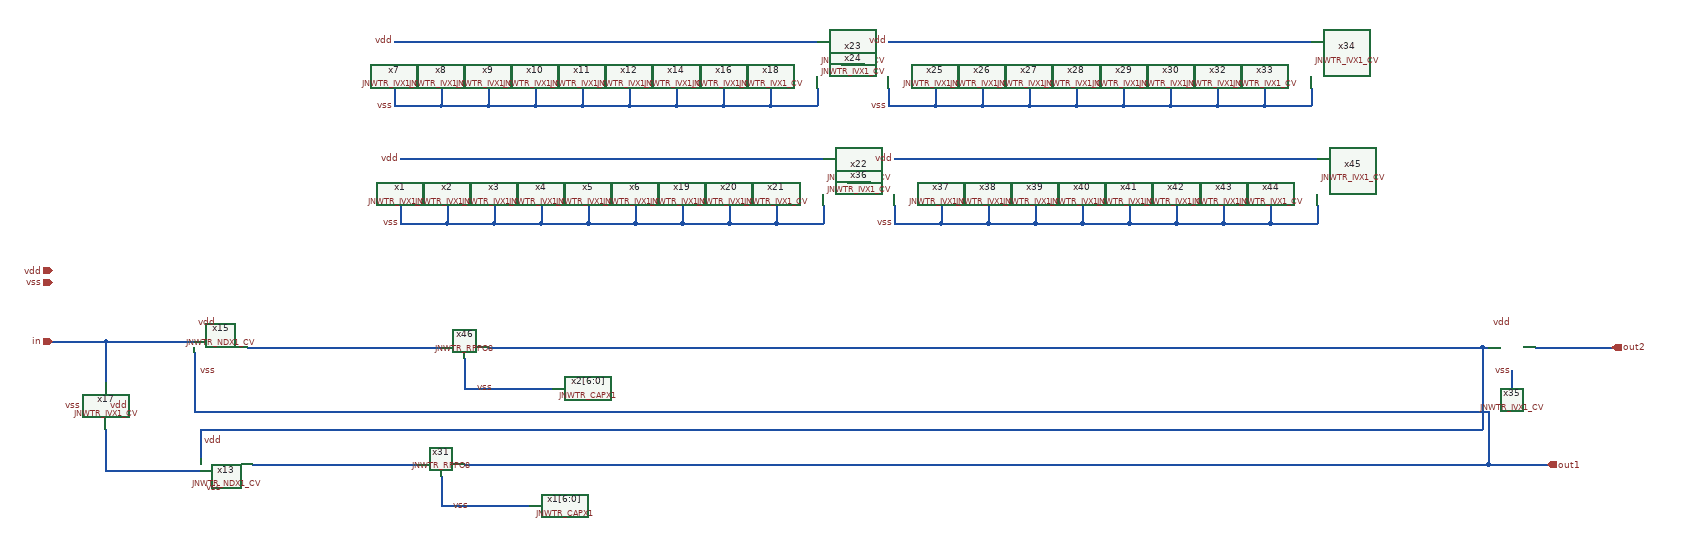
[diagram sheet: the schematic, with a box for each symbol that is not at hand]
v {xschem version=3.4.5 file_version=1.2
}
G {}
K {}
V {}
S {}
E {}
N 170 -220 170 -150 {
lab=#net1}
N 170 -150 330 -150 {
lab=#net1}
N 170 -370 320 -370 {
lab=in}
N 170 -370 170 -300 {
lab=in}
N 80 -370 170 -370 {
lab=in}
N 320 -250 2520 -250 {
lab=out1}
N 320 -350 320 -250 {
lab=out1}
N 330 -220 330 -170 {
lab=#net2}
N 2560 -320 2560 -290 {
lab=vss}
N 2520 -250 2520 -160 {
lab=out1}
N 660 -800 660 -770 {
lab=vss}
N 740 -800 740 -770 {
lab=vss}
N 820 -800 820 -770 {
lab=vss}
N 900 -800 900 -770 {
lab=vss}
N 980 -800 980 -770 {
lab=vss}
N 1060 -800 1060 -770 {
lab=vss}
N 980 -770 1060 -770 {
lab=vss}
N 660 -770 740 -770 {
lab=vss}
N 740 -770 820 -770 {
lab=vss}
N 820 -770 900 -770 {
lab=vss}
N 900 -770 980 -770 {
lab=vss}
N 2510 -360 2510 -220 {
lab=#net2}
N 2520 -160 2620 -160 {
lab=out1}
N 2600 -360 2730 -360 {
lab=out2}
N 1140 -800 1140 -770 {
lab=vss}
N 1220 -800 1220 -770 {
lab=vss}
N 1220 -770 1300 -770 {
lab=vss}
N 1060 -770 1140 -770 {
lab=vss}
N 1140 -770 1220 -770 {
lab=vss}
N 660 -880 1380 -880 {
lab=vdd}
N 1300 -770 1380 -770 {
lab=vss}
N 1300 -800 1300 -770 {
lab=vss}
N 1380 -800 1380 -770 {
lab=vss}
N 740 -140 740 -90 {
lab=vss}
N 740 -90 890 -90 {
lab=vss}
N 2510 -360 2520 -360 {
lab=#net2}
N 330 -220 2510 -220 {
lab=#net2}
N 670 -600 670 -570 {
lab=vss}
N 750 -600 750 -570 {
lab=vss}
N 830 -600 830 -570 {
lab=vss}
N 910 -600 910 -570 {
lab=vss}
N 990 -600 990 -570 {
lab=vss}
N 1070 -600 1070 -570 {
lab=vss}
N 990 -570 1070 -570 {
lab=vss}
N 670 -570 750 -570 {
lab=vss}
N 750 -570 830 -570 {
lab=vss}
N 830 -570 910 -570 {
lab=vss}
N 910 -570 990 -570 {
lab=vss}
N 1150 -600 1150 -570 {
lab=vss}
N 1230 -600 1230 -570 {
lab=vss}
N 1230 -570 1310 -570 {
lab=vss}
N 1070 -570 1150 -570 {
lab=vss}
N 1150 -570 1230 -570 {
lab=vss}
N 670 -680 1390 -680 {
lab=vdd}
N 1310 -570 1390 -570 {
lab=vss}
N 1310 -600 1310 -570 {
lab=vss}
N 1390 -600 1390 -570 {
lab=vss}
N 1500 -800 1500 -770 {
lab=vss}
N 1580 -800 1580 -770 {
lab=vss}
N 1660 -800 1660 -770 {
lab=vss}
N 1740 -800 1740 -770 {
lab=vss}
N 1820 -800 1820 -770 {
lab=vss}
N 1900 -800 1900 -770 {
lab=vss}
N 1820 -770 1900 -770 {
lab=vss}
N 1500 -770 1580 -770 {
lab=vss}
N 1580 -770 1660 -770 {
lab=vss}
N 1660 -770 1740 -770 {
lab=vss}
N 1740 -770 1820 -770 {
lab=vss}
N 1980 -800 1980 -770 {
lab=vss}
N 2060 -800 2060 -770 {
lab=vss}
N 2060 -770 2140 -770 {
lab=vss}
N 1900 -770 1980 -770 {
lab=vss}
N 1980 -770 2060 -770 {
lab=vss}
N 1500 -880 2220 -880 {
lab=vdd}
N 2140 -770 2220 -770 {
lab=vss}
N 2140 -800 2140 -770 {
lab=vss}
N 2220 -800 2220 -770 {
lab=vss}
N 1510 -600 1510 -570 {
lab=vss}
N 1590 -600 1590 -570 {
lab=vss}
N 1670 -600 1670 -570 {
lab=vss}
N 1750 -600 1750 -570 {
lab=vss}
N 1830 -600 1830 -570 {
lab=vss}
N 1910 -600 1910 -570 {
lab=vss}
N 1830 -570 1910 -570 {
lab=vss}
N 1510 -570 1590 -570 {
lab=vss}
N 1590 -570 1670 -570 {
lab=vss}
N 1670 -570 1750 -570 {
lab=vss}
N 1750 -570 1830 -570 {
lab=vss}
N 1990 -600 1990 -570 {
lab=vss}
N 2070 -600 2070 -570 {
lab=vss}
N 2070 -570 2150 -570 {
lab=vss}
N 1910 -570 1990 -570 {
lab=vss}
N 1990 -570 2070 -570 {
lab=vss}
N 1510 -680 2230 -680 {
lab=vdd}
N 2150 -570 2230 -570 {
lab=vss}
N 2150 -600 2150 -570 {
lab=vss}
N 2230 -600 2230 -570 {
lab=vss}
N 1430 -640 1470 -640 {
lab=#net3}
N 1420 -840 1460 -840 {
lab=#net4}
N 420 -160 700 -160 {
lab=#net5}
N 780 -160 2520 -160 {
lab=out1}
N 780 -340 780 -290 {
lab=vss}
N 780 -290 930 -290 {
lab=vss}
N 410 -360 740 -360 {
lab=#net6}
N 820 -360 2510 -360 {
lab=#net2}
C {JNW_TR_SKY130A/JNWTR_NDX1_CV.sym} 330 -150 0 0 {name=x13 }
C {devices/lab_wire.sym} 370 -200 0 0 {name=p26 sig_type=std_logic lab=vdd}
C {devices/lab_wire.sym} 370 -120 0 0 {name=p27 sig_type=std_logic lab=vss
}
C {JNW_TR_SKY130A/JNWTR_NDX1_CV.sym} 320 -350 0 0 {name=x15 }
C {devices/lab_wire.sym} 360 -400 0 0 {name=p28 sig_type=std_logic lab=vdd}
C {devices/lab_wire.sym} 360 -320 0 0 {name=p30 sig_type=std_logic lab=vss
}
C {JNW_TR_SKY130A/JNWTR_IVX1_CV.sym} 170 -300 1 0 {name=x17 }
C {devices/lab_wire.sym} 130 -260 0 0 {name=p31 sig_type=std_logic lab=vss
}
C {devices/lab_wire.sym} 210 -260 0 0 {name=p33 sig_type=std_logic lab=vdd}
C {devices/ipin.sym} 80 -370 0 0 {name=p35 lab=in}
C {JNW_TR_SKY130A/JNWTR_IVX1_CV.sym} 2520 -360 0 0 {name=x35 }
C {devices/lab_wire.sym} 2560 -320 3 0 {name=p51 sig_type=std_logic lab=vss
}
C {devices/lab_wire.sym} 2560 -400 3 0 {name=p52 sig_type=std_logic lab=vdd}
C {devices/opin.sym} 2620 -160 0 0 {name=p1 lab=out1}
C {devices/opin.sym} 2730 -360 0 0 {name=p2 lab=out2}
C {devices/ipin.sym} 80 -470 0 0 {name=p3 lab=vss}
C {devices/ipin.sym} 80 -490 0 0 {name=p4 lab=vdd}
C {JNW_TR_SKY130A/JNWTR_IVX1_CV.sym} 620 -840 0 0 {name=x7 }
C {devices/lab_wire.sym} 660 -770 0 0 {name=p7 sig_type=std_logic lab=vss
}
C {devices/lab_wire.sym} 660 -880 0 0 {name=p8 sig_type=std_logic lab=vdd}
C {JNW_TR_SKY130A/JNWTR_IVX1_CV.sym} 700 -840 0 0 {name=x8 }
C {JNW_TR_SKY130A/JNWTR_IVX1_CV.sym} 780 -840 0 0 {name=x9 }
C {JNW_TR_SKY130A/JNWTR_IVX1_CV.sym} 860 -840 0 0 {name=x10 }
C {JNW_TR_SKY130A/JNWTR_IVX1_CV.sym} 940 -840 0 0 {name=x11 }
C {JNW_TR_SKY130A/JNWTR_IVX1_CV.sym} 1020 -840 0 0 {name=x12 }
C {JNW_TR_SKY130A/JNWTR_IVX1_CV.sym} 1100 -840 0 0 {name=x14 }
C {JNW_TR_SKY130A/JNWTR_IVX1_CV.sym} 1180 -840 0 0 {name=x16 }
C {JNW_TR_SKY130A/JNWTR_IVX1_CV.sym} 1260 -840 0 0 {name=x18 }
C {JNW_TR_SKY130A/JNWTR_IVX1_CV.sym} 1340 -840 0 0 {name=x23 }
C {JNW_TR_SKY130A/JNWTR_CAPX1.sym} 890 -100 0 0 {name=x1[6:0]}
C {devices/lab_wire.sym} 790 -90 3 0 {name=p45 sig_type=std_logic lab=vss
}
C {JNW_TR_SKY130A/JNWTR_RPPO8.sym} 700 -160 0 0 {name=x31 }
C {JNW_TR_SKY130A/JNWTR_IVX1_CV.sym} 630 -640 0 0 {name=x1 }
C {devices/lab_wire.sym} 670 -570 0 0 {name=p5 sig_type=std_logic lab=vss
}
C {devices/lab_wire.sym} 670 -680 0 0 {name=p6 sig_type=std_logic lab=vdd}
C {JNW_TR_SKY130A/JNWTR_IVX1_CV.sym} 710 -640 0 0 {name=x2 }
C {JNW_TR_SKY130A/JNWTR_IVX1_CV.sym} 790 -640 0 0 {name=x3 }
C {JNW_TR_SKY130A/JNWTR_IVX1_CV.sym} 870 -640 0 0 {name=x4 }
C {JNW_TR_SKY130A/JNWTR_IVX1_CV.sym} 950 -640 0 0 {name=x5 }
C {JNW_TR_SKY130A/JNWTR_IVX1_CV.sym} 1030 -640 0 0 {name=x6 }
C {JNW_TR_SKY130A/JNWTR_IVX1_CV.sym} 1110 -640 0 0 {name=x19 }
C {JNW_TR_SKY130A/JNWTR_IVX1_CV.sym} 1190 -640 0 0 {name=x20 }
C {JNW_TR_SKY130A/JNWTR_IVX1_CV.sym} 1270 -640 0 0 {name=x21 }
C {JNW_TR_SKY130A/JNWTR_IVX1_CV.sym} 1350 -640 0 0 {name=x22 }
C {JNW_TR_SKY130A/JNWTR_IVX1_CV.sym} 1460 -840 0 0 {name=x24 }
C {devices/lab_wire.sym} 1500 -770 0 0 {name=p9 sig_type=std_logic lab=vss
}
C {devices/lab_wire.sym} 1500 -880 0 0 {name=p10 sig_type=std_logic lab=vdd}
C {JNW_TR_SKY130A/JNWTR_IVX1_CV.sym} 1540 -840 0 0 {name=x25 }
C {JNW_TR_SKY130A/JNWTR_IVX1_CV.sym} 1620 -840 0 0 {name=x26 }
C {JNW_TR_SKY130A/JNWTR_IVX1_CV.sym} 1700 -840 0 0 {name=x27 }
C {JNW_TR_SKY130A/JNWTR_IVX1_CV.sym} 1780 -840 0 0 {name=x28 }
C {JNW_TR_SKY130A/JNWTR_IVX1_CV.sym} 1860 -840 0 0 {name=x29 }
C {JNW_TR_SKY130A/JNWTR_IVX1_CV.sym} 1940 -840 0 0 {name=x30 }
C {JNW_TR_SKY130A/JNWTR_IVX1_CV.sym} 2020 -840 0 0 {name=x32 }
C {JNW_TR_SKY130A/JNWTR_IVX1_CV.sym} 2100 -840 0 0 {name=x33 }
C {JNW_TR_SKY130A/JNWTR_IVX1_CV.sym} 2180 -840 0 0 {name=x34 }
C {JNW_TR_SKY130A/JNWTR_IVX1_CV.sym} 1470 -640 0 0 {name=x36 }
C {devices/lab_wire.sym} 1510 -570 0 0 {name=p11 sig_type=std_logic lab=vss
}
C {devices/lab_wire.sym} 1510 -680 0 0 {name=p12 sig_type=std_logic lab=vdd}
C {JNW_TR_SKY130A/JNWTR_IVX1_CV.sym} 1550 -640 0 0 {name=x37 }
C {JNW_TR_SKY130A/JNWTR_IVX1_CV.sym} 1630 -640 0 0 {name=x38 }
C {JNW_TR_SKY130A/JNWTR_IVX1_CV.sym} 1710 -640 0 0 {name=x39 }
C {JNW_TR_SKY130A/JNWTR_IVX1_CV.sym} 1790 -640 0 0 {name=x40 }
C {JNW_TR_SKY130A/JNWTR_IVX1_CV.sym} 1870 -640 0 0 {name=x41 }
C {JNW_TR_SKY130A/JNWTR_IVX1_CV.sym} 1950 -640 0 0 {name=x42 }
C {JNW_TR_SKY130A/JNWTR_IVX1_CV.sym} 2030 -640 0 0 {name=x43 }
C {JNW_TR_SKY130A/JNWTR_IVX1_CV.sym} 2110 -640 0 0 {name=x44 }
C {JNW_TR_SKY130A/JNWTR_IVX1_CV.sym} 2190 -640 0 0 {name=x45 }
C {JNW_TR_SKY130A/JNWTR_CAPX1.sym} 930 -300 0 0 {name=x2[6:0]}
C {devices/lab_wire.sym} 830 -290 3 0 {name=p13 sig_type=std_logic lab=vss
}
C {JNW_TR_SKY130A/JNWTR_RPPO8.sym} 740 -360 0 0 {name=x46 }
